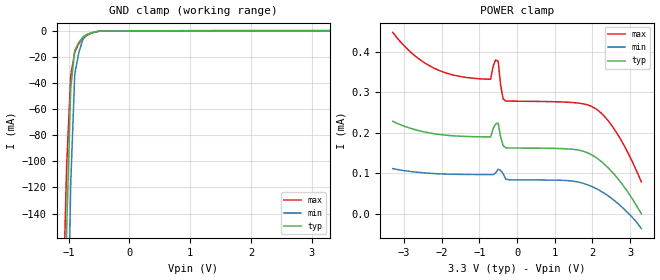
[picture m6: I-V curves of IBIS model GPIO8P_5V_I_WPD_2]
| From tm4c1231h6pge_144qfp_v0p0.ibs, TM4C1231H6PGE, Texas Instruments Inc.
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|   Model Cell GPIO8P_5V_I_WPD_2
[Model]   GPIO8P_5V_I_WPD_2
Model_type   Input
Polarity   Non-Inverting
Vinl =  0.8
Vinh =  2
C_comp   4.711578p   4.034737p   5.423069p
[Model Spec]
Vinl   0.8   0.8   0.8
Vinh   2   2   2
[Temperature Range]   25   125   -40
[Voltage Range]   3.3   2.97   3.63
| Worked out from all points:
|   GND clamp passes 1 mA (typ) near -0.59 V on its own axis
| Nom Voltages:
|   VDDC=1.2, VDD=3.3, GND=0
| Min Voltages:
|   VDDC=1.08, VDD=2.97, GND=0
| Max Voltages:
|   VDDC=1.32, VDD=3.63, GND=0
[POWER_clamp]
|   voltage   I(typ)   I(min)   I(max)
-3.3V     228.1uA    111.4uA    447.3uA
-2.567V   204.1uA    101.7uA    379.3uA
-1.767V   192.9uA    97.66uA    344uA
-700mV    189.6uA    96.73uA    331.6uA
-633.3mV  210.3uA    96.72uA    364.6uA
-500mV    223.8uA    109.9uA    376.2uA
-433.3mV  188.6uA    107uA      315.7uA
-300mV    162.6uA    85.5uA     278uA
1.5V      158.9uA    80.38uA    274.2uA
2.1V      138.6uA    62.26uA    258.5uA
2.7V      84.22uA    23.72uA    191.6uA
3.3V      -66.68pA   -36.61uA   78.8uA
[GND_clamp]
|   voltage   I(typ)   I(min)   I(max)
-3.3V     -16.3A     -15.26A    -17.13A
-1.1V     -340.4mA   -570.5mA   -222.8mA
-1.033V   -152.7mA   -296.8mA   -103.3mA
-966.7mV  -44.17mA   -117.7mA   -34.4mA
-900mV    -14.76mA   -33.12mA   -16.13mA
-833.3mV  -8.747mA   -16.68mA   -9.835mA
-766.7mV  -4.724mA   -6.556mA   -5.587mA
-700mV    -2.687mA   -2.751mA   -3.392mA
-566.7mV  -740.3uA   -760.2uA   -832uA
-433.3mV  -123uA     -131.1uA   -147.2uA
3.3V      162.1uA    87.67uA    277.3uA
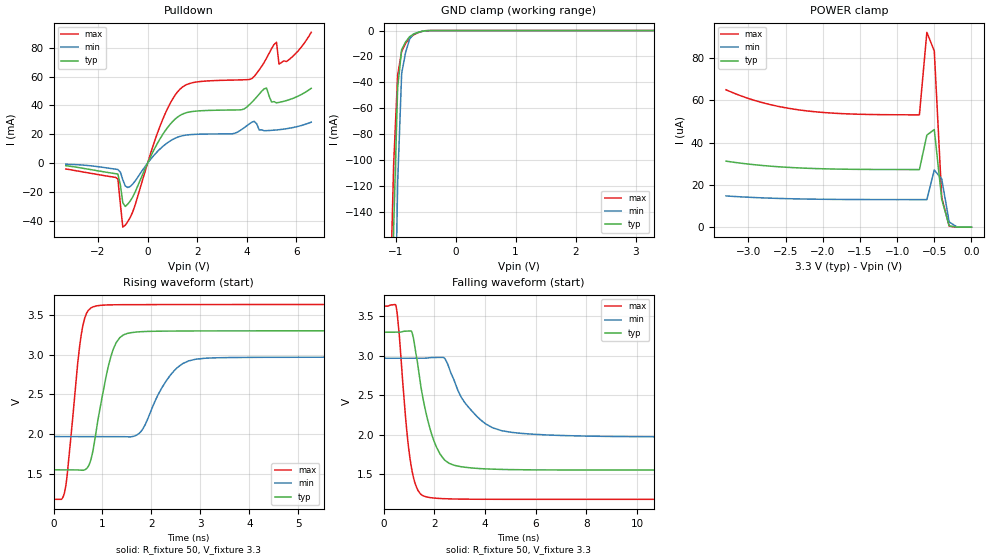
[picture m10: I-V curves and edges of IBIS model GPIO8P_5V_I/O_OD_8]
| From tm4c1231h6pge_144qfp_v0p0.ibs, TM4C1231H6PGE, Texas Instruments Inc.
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|   Model Cell GPIO8P_5V_I/O_OD_8
[Model]   GPIO8P_5V_I/O_OD_8
Model_type   I/O_open_drain
Polarity   Inverting
Enable   Active-Low
Vinl =  0.8
Vinh =  2
Cref =  15.0000pF
Rref =  100.0000M
Vref =  0V
Vmeas =  1.65
C_comp   4.711578p   4.034737p   5.423069p
[Model Spec]
Vinl   0.8   0.8   0.8
Vinh   2   2   2
[Temperature Range]   25   125   -40
[Voltage Range]   3.3   2.97   3.63
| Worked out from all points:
|   slope of the pulldown table from 0 to 0.495 V, typ, clamps not added: 29.7 ohm
|   GND clamp passes 1 mA (typ) near -0.59 V on its own axis
|   rising waveform, R_fixture 50, V_fixture 3.3: 20-80 % time 324ps typ, 517ps min, 232ps max; typ from 1.55 V to 3.3 V
|   falling waveform, R_fixture 50, V_fixture 3.3: 20-80 % time 692ps typ, 1.23ns min, 406ps max; typ from 3.3 V to 1.55 V
| Nom Voltages:
|   VDDC=1.2, VDD=3.3, GND=0
| Min Voltages:
|   VDDC=1.08, VDD=2.97, GND=0
| Max Voltages:
|   VDDC=1.32, VDD=3.63, GND=0
[POWER_clamp]
|   voltage   I(typ)   I(min)   I(max)
-3.3V     31.22uA    14.76uA    64.95uA
-3.1V     30.25uA    14.33uA    62.09uA
-2.8V     29.13uA    13.84uA    58.77uA
-2.3V     27.98uA    13.34uA    55.36uA
-1.7V     27.4uA     13.1uA     53.62uA
-700mV    27.24uA    13.03uA    53.12uA
-600mV    43.52uA    13.03uA    92.14uA
-500mV    46.16uA    27.05uA    83.3uA
-400mV    13.21uA    22.74uA    13.98uA
-300mV    630.7nA    2.501uA    480.9nA
-200mV    23.21nA    190.8nA    10.65nA
0V        660.3pA    10.19nA    564.9pA
[Pulldown]
|   voltage   I(typ)   I(min)   I(max)
-3.3V     -1.804mA   -768.9uA   -4.029mA
-1.2V     -7.576mA   -4.438mA   -10.94mA
-1V       -27.56mA   -11.61mA   -44.39mA
-700mV    -26.23mA   -16.15mA   -37.6mA
500mV     16.83mA    9.794mA    25.59mA
1.3V      32.99mA    18.5mA     51.14mA
3.5V      36.85mA    20.6mA     57.6mA
4.2V      42.1mA     28.33mA    58.55mA
4.8V      51.96mA    22.52mA    72.86mA
5.2V      41.77mA    23mA       83.78mA
5.3V      42.1mA     23.17mA    68.63mA
6.6V      51.87mA    28.39mA    90.67mA
[GND_clamp]
|   voltage   I(typ)   I(min)   I(max)
-3.3V     -16.3A     -15.26A    -17.13A
-1.1V     -340.4mA   -570.5mA   -222.8mA
-1.033V   -152.7mA   -296.8mA   -103.3mA
-966.7mV  -44.18mA   -117.7mA   -34.4mA
-900mV    -14.77mA   -33.12mA   -16.14mA
-833.3mV  -8.752mA   -16.68mA   -9.833mA
-766.7mV  -4.716mA   -6.551mA   -5.563mA
-700mV    -2.657mA   -2.741mA   -3.333mA
-566.7mV  -672.8uA   -727.2uA   -724.4uA
-433.3mV  -51.87uA   -90.8uA    -37.79uA
3.3V      660.3pA    5.308uA    422.7pA
[Ramp]
| variable   typ   min   max
dV/dt_f  1.0583429/0.69409355n 0.60650749/1.2284824n  1.4815153/0.407993n
dV/dt_r  1.1099303/0.78949909n 0.75855304/1.8220444n  1.4680093/0.43078817n
R_load = 50
[Rising Waveform]
R_fixture = 50
V_fixture = 3.3
V_fixture_min = 2.97
V_fixture_max = 3.63
|   time   V(typ)   V(min)   V(max)
0s        1.553V     1.971V     1.183V
228.9ps   1.553V     1.971V     1.278V
565.1ps   1.548V     1.971V     3.248V
738.6ps   1.634V     1.971V     3.573V
859.6ps   1.992V     1.971V     3.61V
1.22ns    3.068V     1.971V     3.626V
1.67ns    3.283V     1.982V     3.628V
2.46ns    3.297V     2.795V     3.629V
3.093ns   3.298V     2.955V     3.629V
20.17ns   3.3V       2.97V      3.63V
[Falling Waveform]
R_fixture = 50
V_fixture = 3.3
V_fixture_min = 2.97
V_fixture_max = 3.63
|   time   V(typ)   V(min)   V(max)
0s        3.3V       2.97V      3.63V
490.6ps   3.3V       2.97V      3.627V
1.062ns   3.316V     2.97V      1.651V
1.299ns   2.986V     2.97V      1.333V
1.561ns   2.445V     2.97V      1.226V
2.222ns   1.757V     2.982V     1.193V
3.023ns   1.597V     2.501V     1.185V
4.016ns   1.568V     2.141V     1.183V
5.4ns     1.557V     2.019V     1.182V
20.17ns   1.553V     1.971V     1.182V
